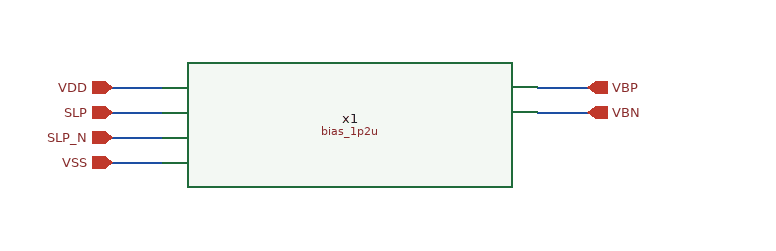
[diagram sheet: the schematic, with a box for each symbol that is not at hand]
v {xschem version=3.4.6 file_version=1.2}
G {}
K {}
V {}
S {}
E {}
N 380 460 420 460 {lab=VDD}
N 380 480 420 480 {lab=SLP}
N 380 500 420 500 {lab=SLP_N}
N 380 520 420 520 {lab=VSS}
N 720 460 760 460 {lab=VBP}
N 720 480 760 480 {lab=VBN}
C {LELO_TORD_SKY130A/bias_1p2u.sym} 570 490 0 0 {name=x1}
C {devices/ipin.sym} 380 460 0 0 {name=p1 lab=VDD}
C {devices/ipin.sym} 380 480 0 0 {name=p2 lab=SLP}
C {devices/ipin.sym} 380 500 0 0 {name=p3 lab=SLP_N}
C {devices/ipin.sym} 380 520 0 0 {name=p4 lab=VSS}
C {devices/opin.sym} 760 460 0 0 {name=p5 lab=VBP}
C {devices/opin.sym} 760 480 0 0 {name=p6 lab=VBN}
